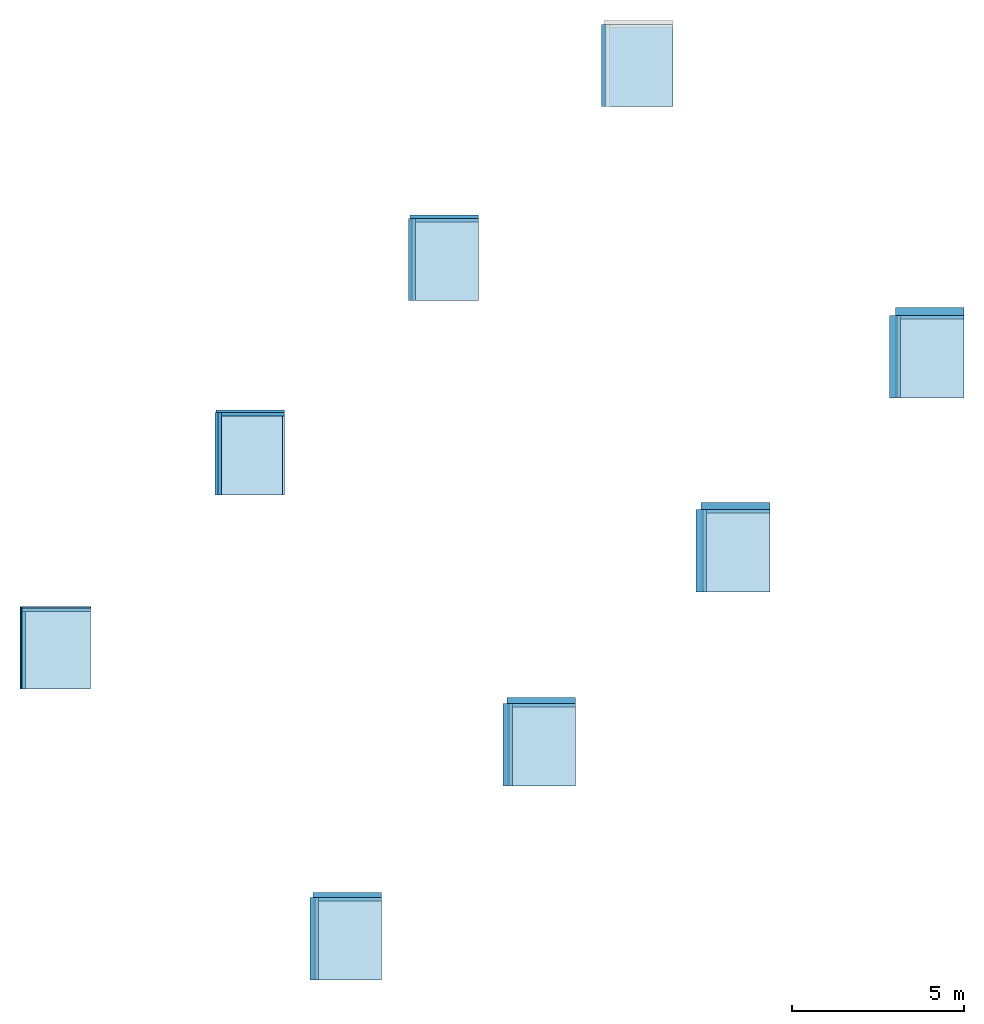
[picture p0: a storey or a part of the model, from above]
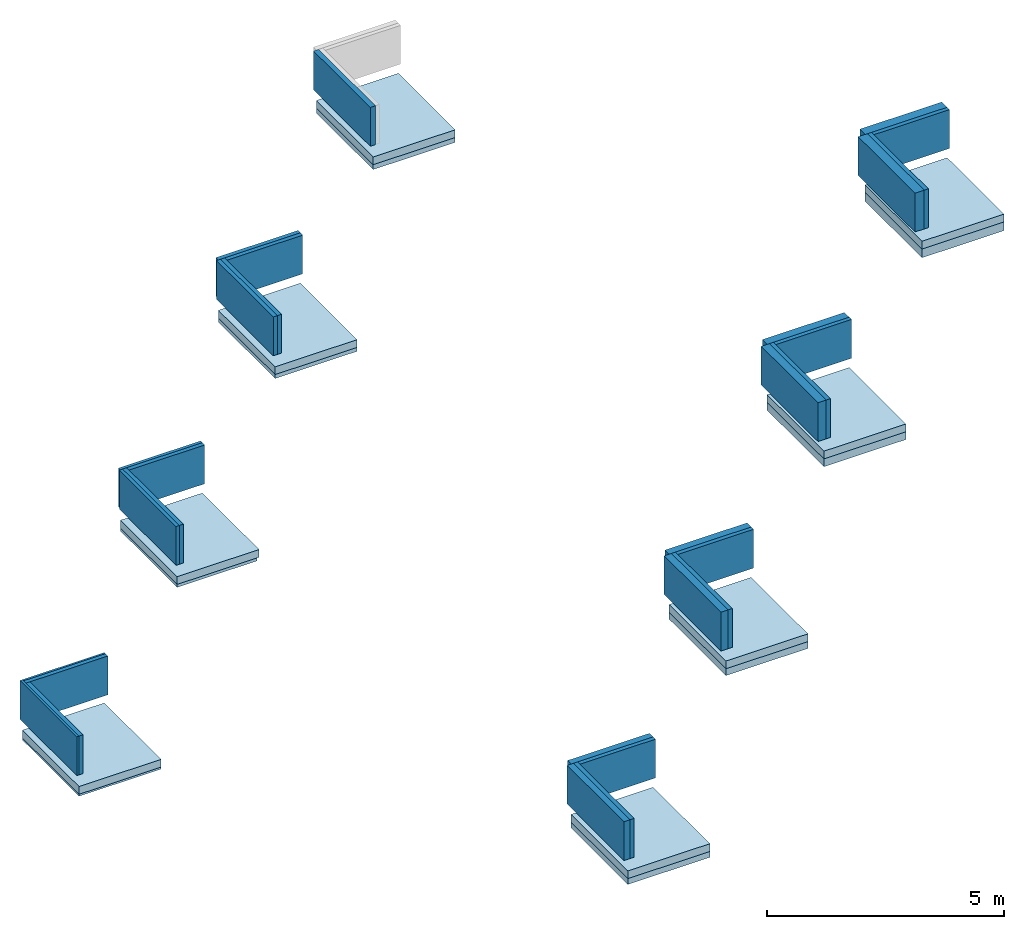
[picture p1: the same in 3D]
Properties of the parts of a building model (IFC2X3), part 2 of 2

# IfcWallStandardCase: Basic Wall:NLRS_41_WA_Heraklith Tektalan A2 SmartTec 125x1000x600mm, Basic Wall:NLRS_41_WA_Heraklith Tektalan A2 SmartTec 125x1000x600mm:929720
Type - Pset_Wall Schedule LOD400 - panelen per pallet: 8; Assembly Code: 41.10; Type Image: Raster image: Heraklith Tektalan A2.jpg; Model: Heraklith® | Tektalan A2 SmartTec is een A2 houtwolcementpaneel gecombineerd met een steenwol-plaat.; Manufacturer: Knauf Insulation B.V.; URL: www.heraklith.nl; Description: Tektalan A2 SmartTec - 125mm; phone: +31(0)162-421245; email: customerservice.nl@knaufinsulation.com; product URL: https://heraklith.nl/houtwol-producten/tektalan-a2-smarttec; warmteweerstand: 3,50 (m2.K/W); NLRS_C_Code_Brandklasse: A2-s1,d0; brandweerstand: REI 120/180 mits verwerkt tegen massief beton conform classificatierapport nr 18203 / 18204; geluidsabsorbtie: 1,00; DoP: W4302GPCPR; NLRS_C_content_creator: Knauf Insulation; NLRS_C_content_versie: V1.0; gewicht KG/M2: 19.5; pallet m2: 4.8 m2; vezelbreedte: standaard 2mm optie: 1mm; kleur: standaard natuurtint optie: Wit (RAL9003) / RAL; Druksterkte kPa: 30; Chloride gehalte: Cl3; Tolerantie: Dikte (T): (T1) +3/-2; Tolerantie: Lengte (L): (L2) +3/-5; Tolerantie: Breedte (W): (W1) +3/-3; Tolerantie: Haaksheid (S): (S2) ≤2; Tolerantie: Vlakheid (P): (P1) ≤6; Randafwerking: Isolatie: n.v.t.; Randafwerking: Houtwol: Facet: 5mm; CE-codering: WW-C2-EN 13168-L2-W1-T1-S2-P1-CS(10/Y)30-TR7,5-Cl3
Classification: 41.10 (Uniformat)
Pset_WallCommon - IsExternal: yes; ExtendToStructure: no; LoadBearing: no
Wall Schedule LOD200 - Type: Basic Wall: NLRS_41_WA_Heraklith Tektalan A2 SmartTec 125x1000x600mm
Pset_Wall Schedule LOD400 - Type: Basic Wall: NLRS_41_WA_Heraklith Tektalan A2 SmartTec 125x1000x600mm

# IfcWallStandardCase: Basic Wall:NLRS_41_WA_Heraklith Tektalan A2 SmartTec 150x1000x600mm, Basic Wall:NLRS_41_WA_Heraklith Tektalan A2 SmartTec 150x1000x600mm:929828
In: 00 begane grond
Type - PredefinedType: STANDARD; Material: Heraklith® I Tektalan A2 - Steenwol 140 mm, Heraklith® I Tektalan A2 - Houtwollaag - 1000x600mm 10 mm
Type - Pset_ElementShading - Roughness: 304.8 mm
Type - Pset_ManufacturerTypeInformation - Manufacturer: Knauf Insulation B.V.
Type - Pset_ProductRequirements - Category: Walls
Type - Pset_QuantityTakeOff - Reference: Basic Wall:NLRS_41_WA_Heraklith Tektalan A2 SmartTec 150x1000x600mm
Type - Pset_ReinforcementBarPitchOfWall - Description: Tektalan A2 SmartTec - 150mm; Reference: Basic Wall:NLRS_41_WA_Heraklith Tektalan A2 SmartTec 150x1000x600mm
Type - Pset_WallCommon - IsExternal: no; Reference: Basic Wall:NLRS_41_WA_Heraklith Tektalan A2 SmartTec 150x1000x600mm; ThermalTransmittance: 0.236111 kg/K/s3
Type - Wall Schedule LOD200 - Assembly Code: 41.10; Type Image: Raster image: Heraklith Tektalan A2.jpg; Model: Heraklith® | Tektalan A2 SmartTec is een A2 houtwolcementpaneel gecombineerd met een steenwol-plaat.; Manufacturer: Knauf Insulation B.V.; URL: www.heraklith.nl; Description: Tektalan A2 SmartTec - 150mm; phone: +31(0)162-421245; email: customerservice.nl@knaufinsulation.com; product URL: https://heraklith.nl/houtwol-producten/tektalan-a2-smarttec; warmteweerstand: 4,20 (m2.K/W); NLRS_C_Code_Brandklasse: A2-s1,d0; brandweerstand: REI 120/180 mits verwerkt tegen massief beton conform classificatierapport nr 18203 / 18204; geluidsabsorbtie: 1,00; DoP: W4302GPCPR; NLRS_C_content_creator: Knauf Insulation; NLRS_C_content_versie: V1.0
Type - Pset_Wall Schedule LOD400 - panelen per pallet: 7; Assembly Code: 41.10; Type Image: Raster image: Heraklith Tektalan A2.jpg; Model: Heraklith® | Tektalan A2 SmartTec is een A2 houtwolcementpaneel gecombineerd met een steenwol-plaat.; Manufacturer: Knauf Insulation B.V.; URL: www.heraklith.nl; Description: Tektalan A2 SmartTec - 150mm; phone: +31(0)162-421245; email: customerservice.nl@knaufinsulation.com; product URL: https://heraklith.nl/houtwol-producten/tektalan-a2-smarttec; warmteweerstand: 4,20 (m2.K/W); NLRS_C_Code_Brandklasse: A2-s1,d0; brandweerstand: REI 120/180 mits verwerkt tegen massief beton conform classificatierapport nr 18203 / 18204; geluidsabsorbtie: 1,00; DoP: W4302GPCPR; NLRS_C_content_creator: Knauf Insulation; NLRS_C_content_versie: V1.0; gewicht KG/M2: 22.5; pallet m2: 4.2 m2; vezelbreedte: standaard 2mm optie: 1mm; kleur: standaard natuurtint optie: Wit (RAL9003) / RAL; Druksterkte kPa: 30; Chloride gehalte: Cl3; Tolerantie: Dikte (T): (T1) +3/-2; Tolerantie: Lengte (L): (L2) +3/-5; Tolerantie: Breedte (W): (W1) +3/-3; Tolerantie: Haaksheid (S): (S2) ≤2; Tolerantie: Vlakheid (P): (P1) ≤6; Randafwerking: Isolatie: n.v.t.; Randafwerking: Houtwol: Facet: 5mm; CE-codering: WW-C2-EN 13168-L2-W1-T1-S2-P1-CS(10/Y)30-TR7,5-Cl3
Classification: 41.10 (Uniformat)
Pset_WallCommon - IsExternal: yes; ExtendToStructure: no; LoadBearing: no
Wall Schedule LOD200 - Type: Basic Wall: NLRS_41_WA_Heraklith Tektalan A2 SmartTec 150x1000x600mm
Pset_Wall Schedule LOD400 - Type: Basic Wall: NLRS_41_WA_Heraklith Tektalan A2 SmartTec 150x1000x600mm

# IfcWallStandardCase: Basic Wall:NLRS_41_WA_Heraklith Tektalan A2 SmartTec 175x1000x600mm, Basic Wall:NLRS_41_WA_Heraklith Tektalan A2 SmartTec 175x1000x600mm:929852
In: 00 begane grond
Type - PredefinedType: STANDARD; Material: Heraklith® I Tektalan A2 - Steenwol 165 mm, Heraklith® I Tektalan A2 - Houtwollaag - 1000x600mm 10 mm
Type - Pset_ElementShading - Roughness: 304.8 mm
Type - Pset_ManufacturerTypeInformation - Manufacturer: Knauf Insulation B.V.
Type - Pset_ProductRequirements - Category: Walls
Type - Pset_QuantityTakeOff - Reference: Basic Wall:NLRS_41_WA_Heraklith Tektalan A2 SmartTec 175x1000x600mm
Type - Pset_ReinforcementBarPitchOfWall - Description: Tektalan A2 SmartTec - 175mm; Reference: Basic Wall:NLRS_41_WA_Heraklith Tektalan A2 SmartTec 175x1000x600mm
Type - Pset_WallCommon - IsExternal: no; Reference: Basic Wall:NLRS_41_WA_Heraklith Tektalan A2 SmartTec 175x1000x600mm; ThermalTransmittance: 0.201183 kg/K/s3
Type - Wall Schedule LOD200 - Assembly Code: 41.10; Type Image: Raster image: Heraklith Tektalan A2.jpg; Model: Heraklith® | Tektalan A2 SmartTec is een A2 houtwolcementpaneel gecombineerd met een steenwol-plaat.; Manufacturer: Knauf Insulation B.V.; URL: www.heraklith.nl; Description: Tektalan A2 SmartTec - 175mm; phone: +31(0)162-421245; email: customerservice.nl@knaufinsulation.com; product URL: https://heraklith.nl/houtwol-producten/tektalan-a2-smarttec; warmteweerstand: 4,95 (m2.K/W); NLRS_C_Code_Brandklasse: A2-s1,d0; brandweerstand: REI 120/180 mits verwerkt tegen massief beton conform classificatierapport nr 18203 / 18204; geluidsabsorbtie: 1,00; DoP: W4302GPCPR; NLRS_C_content_creator: Knauf Insulation; NLRS_C_content_versie: V1.0
Type - Pset_Wall Schedule LOD400 - panelen per pallet: 6; Assembly Code: 41.10; Type Image: Raster image: Heraklith Tektalan A2.jpg; Model: Heraklith® | Tektalan A2 SmartTec is een A2 houtwolcementpaneel gecombineerd met een steenwol-plaat.; Manufacturer: Knauf Insulation B.V.; URL: www.heraklith.nl; Description: Tektalan A2 SmartTec - 175mm; phone: +31(0)162-421245; email: customerservice.nl@knaufinsulation.com; product URL: https://heraklith.nl/houtwol-producten/tektalan-a2-smarttec; warmteweerstand: 4,95 (m2.K/W); NLRS_C_Code_Brandklasse: A2-s1,d0; brandweerstand: REI 120/180 mits verwerkt tegen massief beton conform classificatierapport nr 18203 / 18204; geluidsabsorbtie: 1,00; DoP: W4302GPCPR; NLRS_C_content_creator: Knauf Insulation; NLRS_C_content_versie: V1.0; gewicht KG/M2: 25; pallet m2: 3.6 m2; vezelbreedte: standaard 2mm optie: 1mm; kleur: standaard natuurtint optie: Wit (RAL9003) / RAL; Druksterkte kPa: 30; Chloride gehalte: Cl3; Tolerantie: Dikte (T): (T1) +3/-2; Tolerantie: Lengte (L): (L2) +3/-5; Tolerantie: Breedte (W): (W1) +3/-3; Tolerantie: Haaksheid (S): (S2) ≤2; Tolerantie: Vlakheid (P): (P1) ≤6; Randafwerking: Isolatie: n.v.t.; Randafwerking: Houtwol: Facet: 5mm; CE-codering: WW-C2-EN 13168-L2-W1-T1-S2-P1-CS(10/Y)30-TR7,5-Cl3
Classification: 41.10 (Uniformat)
Pset_WallCommon - IsExternal: yes; ExtendToStructure: no; LoadBearing: no
Wall Schedule LOD200 - Type: Basic Wall: NLRS_41_WA_Heraklith Tektalan A2 SmartTec 175x1000x600mm
Pset_Wall Schedule LOD400 - Type: Basic Wall: NLRS_41_WA_Heraklith Tektalan A2 SmartTec 175x1000x600mm

# IfcWallStandardCase: Basic Wall:NLRS_41_WA_Heraklith Tektalan A2 SmartTec 200x1000x600mm, Basic Wall:NLRS_41_WA_Heraklith Tektalan A2 SmartTec 200x1000x600mm:929877
In: 00 begane grond
Type - PredefinedType: STANDARD; Material: Heraklith® I Tektalan A2 - Steenwol 190 mm, Heraklith® I Tektalan A2 - Houtwollaag - 1000x600mm 10 mm
Type - Pset_ElementShading - Roughness: 304.8 mm
Type - Pset_ManufacturerTypeInformation - Manufacturer: Knauf Insulation B.V.
Type - Pset_ProductRequirements - Category: Walls
Type - Pset_QuantityTakeOff - Reference: Basic Wall:NLRS_41_WA_Heraklith Tektalan A2 SmartTec 200x1000x600mm
Type - Pset_ReinforcementBarPitchOfWall - Description: Tektalan A2 SmartTec - 200mm; Reference: Basic Wall:NLRS_41_WA_Heraklith Tektalan A2 SmartTec 200x1000x600mm
Type - Pset_WallCommon - IsExternal: no; Reference: Basic Wall:NLRS_41_WA_Heraklith Tektalan A2 SmartTec 200x1000x600mm; ThermalTransmittance: 0.175258 kg/K/s3
Type - Wall Schedule LOD200 - Assembly Code: 41.10; Type Image: Raster image: Heraklith Tektalan A2.jpg; Model: Heraklith® | Tektalan A2 SmartTec is een A2 houtwolcementpaneel gecombineerd met een steenwol-plaat.; Manufacturer: Knauf Insulation B.V.; URL: www.heraklith.nl; Description: Tektalan A2 SmartTec - 200mm; phone: +31(0)162-421245; email: customerservice.nl@knaufinsulation.com; product URL: https://heraklith.nl/houtwol-producten/tektalan-a2-smarttec; warmteweerstand: 5,70 (m2.K/W); NLRS_C_Code_Brandklasse: A2-s1,d0; brandweerstand: REI 120/180 mits verwerkt tegen massief beton conform classificatierapport nr 18203 / 18204; geluidsabsorbtie: 0,95; DoP: W4302GPCPR; NLRS_C_content_creator: Knauf Insulation; NLRS_C_content_versie: V1.0
Type - Pset_Wall Schedule LOD400 - panelen per pallet: 5; Assembly Code: 41.10; Type Image: Raster image: Heraklith Tektalan A2.jpg; Model: Heraklith® | Tektalan A2 SmartTec is een A2 houtwolcementpaneel gecombineerd met een steenwol-plaat.; Manufacturer: Knauf Insulation B.V.; URL: www.heraklith.nl; Description: Tektalan A2 SmartTec - 200mm; phone: +31(0)162-421245; email: customerservice.nl@knaufinsulation.com; product URL: https://heraklith.nl/houtwol-producten/tektalan-a2-smarttec; warmteweerstand: 5,70 (m2.K/W); NLRS_C_Code_Brandklasse: A2-s1,d0; brandweerstand: REI 120/180 mits verwerkt tegen massief beton conform classificatierapport nr 18203 / 18204; geluidsabsorbtie: 0,95; DoP: W4302GPCPR; NLRS_C_content_creator: Knauf Insulation; NLRS_C_content_versie: V1.0; gewicht KG/M2: 25.5; pallet m2: 3 m2; vezelbreedte: standaard 2mm optie: 1mm; kleur: standaard natuurtint optie: Wit (RAL9003) / RAL; Druksterkte kPa: 30; Chloride gehalte: Cl3; Tolerantie: Dikte (T): (T1) +3/-2; Tolerantie: Lengte (L): (L2) +3/-5; Tolerantie: Breedte (W): (W1) +3/-3; Tolerantie: Haaksheid (S): (S2) ≤2; Tolerantie: Vlakheid (P): (P1) ≤6; Randafwerking: Isolatie: n.v.t.; Randafwerking: Houtwol: Facet: 5mm; CE-codering: WW-C2-EN 13168-L2-W1-T1-S2-P1-CS(10/Y)30-TR7,5-Cl3
Classification: 41.10 (Uniformat)
Pset_WallCommon - IsExternal: yes; ExtendToStructure: no; LoadBearing: no
Wall Schedule LOD200 - Type: Basic Wall: NLRS_41_WA_Heraklith Tektalan A2 SmartTec 200x1000x600mm
Pset_Wall Schedule LOD400 - Type: Basic Wall: NLRS_41_WA_Heraklith Tektalan A2 SmartTec 200x1000x600mm

# IfcWallStandardCase: Basic Wall:NLRS_41_WA_Heraklith Tektalan A2 SmartTec 225x1000x600mm, Basic Wall:NLRS_41_WA_Heraklith Tektalan A2 SmartTec 225x1000x600mm:929902
In: 00 begane grond
Type - PredefinedType: STANDARD; Material: Heraklith® I Tektalan A2 - Steenwol 215 mm, Heraklith® I Tektalan A2 - Houtwollaag - 1000x600mm 10 mm
Type - Pset_ElementShading - Roughness: 304.8 mm
Type - Pset_ManufacturerTypeInformation - Manufacturer: Knauf Insulation B.V.
Type - Pset_ProductRequirements - Category: Walls
Type - Pset_QuantityTakeOff - Reference: Basic Wall:NLRS_41_WA_Heraklith Tektalan A2 SmartTec 225x1000x600mm
Type - Pset_ReinforcementBarPitchOfWall - Description: Tektalan A2 SmartTec - 225mm; Reference: Basic Wall:NLRS_41_WA_Heraklith Tektalan A2 SmartTec 225x1000x600mm
Type - Pset_WallCommon - IsExternal: no; Reference: Basic Wall:NLRS_41_WA_Heraklith Tektalan A2 SmartTec 225x1000x600mm; ThermalTransmittance: 0.155251 kg/K/s3
Type - Wall Schedule LOD200 - Assembly Code: 41.10; Type Image: Raster image: Heraklith Tektalan A2.jpg; Model: Heraklith® | Tektalan A2 SmartTec is een A2 houtwolcementpaneel gecombineerd met een steenwol-plaat.; Manufacturer: Knauf Insulation B.V.; URL: www.heraklith.nl; Description: Tektalan A2 SmartTec - 225mm; phone: +31(0)162-421245; email: customerservice.nl@knaufinsulation.com; product URL: https://heraklith.nl/houtwol-producten/tektalan-a2-smarttec; warmteweerstand: 6,40 (m2.K/W); NLRS_C_Code_Brandklasse: A2-s1,d0; brandweerstand: REI 120/180 mits verwerkt tegen massief beton conform classificatierapport nr 18203 / 18204; geluidsabsorbtie: 0,95; DoP: W4302GPCPR; NLRS_C_content_creator: Knauf Insulation; NLRS_C_content_versie: V1.0
Type - Pset_Wall Schedule LOD400 - panelen per pallet: 5; Assembly Code: 41.10; Type Image: Raster image: Heraklith Tektalan A2.jpg; Model: Heraklith® | Tektalan A2 SmartTec is een A2 houtwolcementpaneel gecombineerd met een steenwol-plaat.; Manufacturer: Knauf Insulation B.V.; URL: www.heraklith.nl; Description: Tektalan A2 SmartTec - 225mm; phone: +31(0)162-421245; email: customerservice.nl@knaufinsulation.com; product URL: https://heraklith.nl/houtwol-producten/tektalan-a2-smarttec; warmteweerstand: 6,40 (m2.K/W); NLRS_C_Code_Brandklasse: A2-s1,d0; brandweerstand: REI 120/180 mits verwerkt tegen massief beton conform classificatierapport nr 18203 / 18204; geluidsabsorbtie: 0,95; DoP: W4302GPCPR; NLRS_C_content_creator: Knauf Insulation; NLRS_C_content_versie: V1.0; gewicht KG/M2: 31; pallet m2: 3 m2; vezelbreedte: standaard 2mm optie: 1mm; kleur: standaard natuurtint optie: Wit (RAL9003) / RAL; Druksterkte kPa: 30; Chloride gehalte: Cl3; Tolerantie: Dikte (T): (T1) +3/-2; Tolerantie: Lengte (L): (L2) +3/-5; Tolerantie: Breedte (W): (W1) +3/-3; Tolerantie: Haaksheid (S): (S2) ≤2; Tolerantie: Vlakheid (P): (P1) ≤6; Randafwerking: Isolatie: n.v.t.; Randafwerking: Houtwol: Facet: 5mm; CE-codering: WW-C2-EN 13168-L2-W1-T1-S2-P1-CS(10/Y)30-TR7,5-Cl3
Classification: 41.10 (Uniformat)
Pset_WallCommon - IsExternal: yes; ExtendToStructure: no; LoadBearing: no
Wall Schedule LOD200 - Type: Basic Wall: NLRS_41_WA_Heraklith Tektalan A2 SmartTec 225x1000x600mm
Pset_Wall Schedule LOD400 - Type: Basic Wall: NLRS_41_WA_Heraklith Tektalan A2 SmartTec 225x1000x600mm

# IfcWallStandardCase: Basic Wall:NLRS_41_WA_Heraklith Tektalan A2 SmartTec 50x1000x600mm, Basic Wall:NLRS_41_WA_Heraklith Tektalan A2 SmartTec 50x1000x600mm:905813
In: 00 begane grond
Type - PredefinedType: STANDARD; Material: Heraklith® I Tektalan A2 - Steenwol 40 mm, Heraklith® I Tektalan A2 - Houtwollaag - 1000x600mm 10 mm
Type - Pset_ElementShading - Roughness: 304.8 mm
Type - Pset_ManufacturerTypeInformation - Manufacturer: Knauf Insulation B.V.
Type - Pset_ProductRequirements - Category: Walls
Type - Pset_QuantityTakeOff - Reference: Basic Wall:NLRS_41_WA_Heraklith Tektalan A2 SmartTec 50x1000x600mm
Type - Pset_ReinforcementBarPitchOfWall - Description: Tektalan A2 SmartTec - 50mm; Reference: Basic Wall:NLRS_41_WA_Heraklith Tektalan A2 SmartTec 50x1000x600mm
Type - Pset_WallCommon - Reference: Basic Wall:NLRS_41_WA_Heraklith Tektalan A2 SmartTec 50x1000x600mm; ThermalTransmittance: 0.772727 kg/K/s3; IsExternal: no
Type - Wall Schedule LOD200 - Assembly Code: 41.10; Type Image: Raster image: Heraklith Tektalan A2.jpg; Model: Heraklith® | Tektalan A2 SmartTec is een A2 houtwolcementpaneel gecombineerd met een steenwol-plaat.; Manufacturer: Knauf Insulation B.V.; URL: www.heraklith.nl; Description: Tektalan A2 SmartTec - 50mm; phone: +31(0)162-421245; email: customerservice.nl@knaufinsulation.com; product URL: https://heraklith.nl/houtwol-producten/tektalan-a2-smarttec; warmteweerstand: 1,25 (m2.K/W); NLRS_C_Code_Brandklasse: A2-s1,d0; brandweerstand: REI 120/180 mits verwerkt tegen massief beton conform classificatierapport nr 18203 / 18204; geluidsabsorbtie: 0,95; DoP: W4302GPCPR; NLRS_C_content_creator: Knauf Insulation; NLRS_C_content_versie: V1.0
Type - Pset_Wall Schedule LOD400 - Assembly Code: 41.10; Type Image: Raster image: Heraklith Tektalan A2.jpg; Model: Heraklith® | Tektalan A2 SmartTec is een A2 houtwolcementpaneel gecombineerd met een steenwol-plaat.; Manufacturer: Knauf Insulation B.V.; URL: www.heraklith.nl; Description: Tektalan A2 SmartTec - 50mm; phone: +31(0)162-421245; email: customerservice.nl@knaufinsulation.com; product URL: https://heraklith.nl/houtwol-producten/tektalan-a2-smarttec; warmteweerstand: 1,25 (m2.K/W); NLRS_C_Code_Brandklasse: A2-s1,d0; brandweerstand: REI 120/180 mits verwerkt tegen massief beton conform classificatierapport nr 18203 / 18204; geluidsabsorbtie: 0,95; DoP: W4302GPCPR; NLRS_C_content_creator: Knauf Insulation; NLRS_C_content_versie: V1.0; gewicht KG/M2: 11; panelen per pallet: 22; pallet m2: 13.2 m2; vezelbreedte: standaard 2mm optie: 1mm; kleur: standaard natuurtint optie: Wit (RAL9003) / RAL; Druksterkte kPa: 30; Chloride gehalte: Cl3; Tolerantie: Dikte (T): (T1) +3/-2; Tolerantie: Lengte (L): (L2) +3/-5; Tolerantie: Breedte (W): (W1) +3/-3; Tolerantie: Haaksheid (S): (S2) ≤2; Tolerantie: Vlakheid (P): (P1) ≤6; Randafwerking: Isolatie: n.v.t.; Randafwerking: Houtwol: Facet: 5mm; CE-codering: WW-C2-EN 13168-L2-W1-T1-S2-P1-CS(10/Y)30-TR7,5-Cl3
Classification: 41.10 (Uniformat)
Pset_WallCommon - IsExternal: yes; ExtendToStructure: no; LoadBearing: no
Wall Schedule LOD200 - Type: Basic Wall: NLRS_41_WA_Heraklith Tektalan A2 SmartTec 50x1000x600mm
Pset_Wall Schedule LOD400 - Type: Basic Wall: NLRS_41_WA_Heraklith Tektalan A2 SmartTec 50x1000x600mm

# IfcWallStandardCase: Basic Wall:NLRS_41_WA_Heraklith Tektalan A2 SmartTec 75x1000x600mm, Basic Wall:NLRS_41_WA_Heraklith Tektalan A2 SmartTec 75x1000x600mm:929507
In: 00 begane grond
Type - PredefinedType: STANDARD; Material: Heraklith® I Tektalan A2 - Steenwol 65 mm, Heraklith® I Tektalan A2 - Houtwollaag - 1000x600mm 10 mm
Type - Pset_ElementShading - Roughness: 304.8 mm
Type - Pset_ManufacturerTypeInformation - Manufacturer: Knauf Insulation B.V.
Type - Pset_ProductRequirements - Category: Walls
Type - Pset_QuantityTakeOff - Reference: Basic Wall:NLRS_41_WA_Heraklith Tektalan A2 SmartTec 75x1000x600mm
Type - Pset_ReinforcementBarPitchOfWall - Description: Tektalan A2 SmartTec - 75mm; Reference: Basic Wall:NLRS_41_WA_Heraklith Tektalan A2 SmartTec 75x1000x600mm
Type - Pset_WallCommon - IsExternal: no; Reference: Basic Wall:NLRS_41_WA_Heraklith Tektalan A2 SmartTec 75x1000x600mm; ThermalTransmittance: 0.492754 kg/K/s3
Type - Wall Schedule LOD200 - Assembly Code: 41.10; Type Image: Raster image: Heraklith Tektalan A2.jpg; Model: Heraklith® | Tektalan A2 SmartTec is een A2 houtwolcementpaneel gecombineerd met een steenwol-plaat.; Manufacturer: Knauf Insulation B.V.; URL: www.heraklith.nl; Description: Tektalan A2 SmartTec - 75mm; phone: +31(0)162-421245; email: customerservice.nl@knaufinsulation.com; product URL: https://heraklith.nl/houtwol-producten/tektalan-a2-smarttec; warmteweerstand: 2,00 (m2.K/W); NLRS_C_Code_Brandklasse: A2-s1,d0; brandweerstand: REI 120/180 mits verwerkt tegen massief beton conform classificatierapport nr 18203 / 18204; geluidsabsorbtie: 0,95; DoP: W4302GPCPR; NLRS_C_content_creator: Knauf Insulation; NLRS_C_content_versie: V1.0
Type - Pset_Wall Schedule LOD400 - Assembly Code: 41.10; Type Image: Raster image: Heraklith Tektalan A2.jpg; Model: Heraklith® | Tektalan A2 SmartTec is een A2 houtwolcementpaneel gecombineerd met een steenwol-plaat.; Manufacturer: Knauf Insulation B.V.; URL: www.heraklith.nl; Description: Tektalan A2 SmartTec - 75mm; phone: +31(0)162-421245; email: customerservice.nl@knaufinsulation.com; product URL: https://heraklith.nl/houtwol-producten/tektalan-a2-smarttec; warmteweerstand: 2,00 (m2.K/W); NLRS_C_Code_Brandklasse: A2-s1,d0; brandweerstand: REI 120/180 mits verwerkt tegen massief beton conform classificatierapport nr 18203 / 18204; geluidsabsorbtie: 0,95; DoP: W4302GPCPR; NLRS_C_content_creator: Knauf Insulation; NLRS_C_content_versie: V1.0; gewicht KG/M2: 14; panelen per pallet: 14; pallet m2: 8.4 m2; vezelbreedte: standaard 2mm optie: 1mm; kleur: standaard natuurtint optie: Wit (RAL9003) / RAL; Druksterkte kPa: 30; Chloride gehalte: Cl3; Tolerantie: Dikte (T): (T1) +3/-2; Tolerantie: Lengte (L): (L2) +3/-5; Tolerantie: Breedte (W): (W1) +3/-3; Tolerantie: Haaksheid (S): (S2) ≤2; Tolerantie: Vlakheid (P): (P1) ≤6; Randafwerking: Isolatie: n.v.t.; Randafwerking: Houtwol: Facet: 5mm; CE-codering: WW-C2-EN 13168-L2-W1-T1-S2-P1-CS(10/Y)30-TR7,5-Cl3
Classification: 41.10 (Uniformat)
Pset_WallCommon - IsExternal: yes; ExtendToStructure: no; LoadBearing: no
Wall Schedule LOD200 - Type: Basic Wall: NLRS_41_WA_Heraklith Tektalan A2 SmartTec 75x1000x600mm
Pset_Wall Schedule LOD400 - Type: Basic Wall: NLRS_41_WA_Heraklith Tektalan A2 SmartTec 75x1000x600mm

# IfcWallStandardCase: Basic Wall:NLRS_42_WA_Heraklith Tektalan A2 SmartTec 100x1000x600mm, Basic Wall:NLRS_42_WA_Heraklith Tektalan A2 SmartTec 100x1000x600mm:929629
In: 00 begane grond
Type - PredefinedType: STANDARD; Material: Heraklith® I Tektalan A2 - Steenwol 90 mm, Heraklith® I Tektalan A2 - Houtwollaag - 1000x600mm 10 mm
Type - Pset_ElementShading - Roughness: 304.8 mm
Type - Pset_ManufacturerTypeInformation - Manufacturer: Knauf Insulation B.V.
Type - Pset_ProductRequirements - Category: Walls
Type - Pset_QuantityTakeOff - Reference: Basic Wall:NLRS_42_WA_Heraklith Tektalan A2 SmartTec 100x1000x600mm
Type - Pset_ReinforcementBarPitchOfWall - Description: Tektalan A2 SmartTec - 100mm; Reference: Basic Wall:NLRS_42_WA_Heraklith Tektalan A2 SmartTec 100x1000x600mm
Type - Pset_WallCommon - IsExternal: no; Reference: Basic Wall:NLRS_42_WA_Heraklith Tektalan A2 SmartTec 100x1000x600mm; ThermalTransmittance: 0.361702 kg/K/s3
Type - Wall Schedule LOD200 - Assembly Code: 42.10; Type Image: Raster image: Heraklith Tektalan A2.jpg; Model: Heraklith® | Tektalan A2 SmartTec is een A2 houtwolcementpaneel gecombineerd met een steenwol-plaat.; Manufacturer: Knauf Insulation B.V.; URL: www.heraklith.nl; Description: Tektalan A2 SmartTec - 100mm; phone: +31(0)162-421245; email: customerservice.nl@knaufinsulation.com; product URL: https://heraklith.nl/houtwol-producten/tektalan-a2-smarttec; warmteweerstand: 2,75 (m2.K/W); NLRS_C_Code_Brandklasse: A2-s1,d0; brandweerstand: REI 120/180 mits verwerkt tegen massief beton conform classificatierapport nr 18203 / 18204; geluidsabsorbtie: 1,00; DoP: W4302GPCPR; NLRS_C_content_creator: Knauf Insulation; NLRS_C_content_versie: V1.0
Type - Pset_Wall Schedule LOD400 - Assembly Code: 42.10; Type Image: Raster image: Heraklith Tektalan A2.jpg; Model: Heraklith® | Tektalan A2 SmartTec is een A2 houtwolcementpaneel gecombineerd met een steenwol-plaat.; Manufacturer: Knauf Insulation B.V.; URL: www.heraklith.nl; Description: Tektalan A2 SmartTec - 100mm; phone: +31(0)162-421245; email: customerservice.nl@knaufinsulation.com; product URL: https://heraklith.nl/houtwol-producten/tektalan-a2-smarttec; warmteweerstand: 2,75 (m2.K/W); NLRS_C_Code_Brandklasse: A2-s1,d0; brandweerstand: REI 120/180 mits verwerkt tegen massief beton conform classificatierapport nr 18203 / 18204; geluidsabsorbtie: 1,00; DoP: W4302GPCPR; NLRS_C_content_creator: Knauf Insulation; NLRS_C_content_versie: V1.0; gewicht KG/M2: 17; panelen per pallet: 11; pallet m2: 6.6 m2; vezelbreedte: standaard 2mm optie: 1mm; kleur: standaard natuurtint optie: Wit (RAL9003) / RAL; Druksterkte kPa: 30; Chloride gehalte: Cl3; Tolerantie: Dikte (T): (T1) +3/-2; Tolerantie: Lengte (L): (L2) +3/-5; Tolerantie: Breedte (W): (W1) +3/-3; Tolerantie: Haaksheid (S): (S2) ≤2; Tolerantie: Vlakheid (P): (P1) ≤6; Randafwerking: Isolatie: n.v.t.; Randafwerking: Houtwol: Facet: 5mm; CE-codering: WW-C2-EN 13168-L2-W1-T1-S2-P1-CS(10/Y)30-TR7,5-Cl3
Classification: 42.10 (Uniformat)
Pset_WallCommon - ExtendToStructure: no; LoadBearing: no
Wall Schedule LOD200 - Type: Basic Wall: NLRS_42_WA_Heraklith Tektalan A2 SmartTec 100x1000x600mm
Pset_Wall Schedule LOD400 - Type: Basic Wall: NLRS_42_WA_Heraklith Tektalan A2 SmartTec 100x1000x600mm

# IfcWallStandardCase: Basic Wall:NLRS_42_WA_Heraklith Tektalan A2 SmartTec 125x1000x600mm, Basic Wall:NLRS_42_WA_Heraklith Tektalan A2 SmartTec 125x1000x600mm:929729
In: 00 begane grond
Type - PredefinedType: STANDARD; Material: Heraklith® I Tektalan A2 - Steenwol 115 mm, Heraklith® I Tektalan A2 - Houtwollaag - 1000x600mm 10 mm
Type - Pset_ElementShading - Roughness: 304.8 mm
Type - Pset_ManufacturerTypeInformation - Manufacturer: Knauf Insulation B.V.
Type - Pset_ProductRequirements - Category: Walls
Type - Pset_QuantityTakeOff - Reference: Basic Wall:NLRS_42_WA_Heraklith Tektalan A2 SmartTec 125x1000x600mm
Type - Pset_ReinforcementBarPitchOfWall - Description: Tektalan A2 SmartTec - 125mm; Reference: Basic Wall:NLRS_42_WA_Heraklith Tektalan A2 SmartTec 125x1000x600mm
Type - Pset_WallCommon - IsExternal: no; Reference: Basic Wall:NLRS_42_WA_Heraklith Tektalan A2 SmartTec 125x1000x600mm; ThermalTransmittance: 0.285714 kg/K/s3
Type - Wall Schedule LOD200 - Assembly Code: 42.10; Type Image: Raster image: Heraklith Tektalan A2.jpg; Model: Heraklith® | Tektalan A2 SmartTec is een A2 houtwolcementpaneel gecombineerd met een steenwol-plaat.; Manufacturer: Knauf Insulation B.V.; URL: www.heraklith.nl; Description: Tektalan A2 SmartTec - 125mm; phone: +31(0)162-421245; email: customerservice.nl@knaufinsulation.com; product URL: https://heraklith.nl/houtwol-producten/tektalan-a2-smarttec; warmteweerstand: 3,50 (m2.K/W); NLRS_C_Code_Brandklasse: A2-s1,d0; brandweerstand: REI 120/180 mits verwerkt tegen massief beton conform classificatierapport nr 18203 / 18204; geluidsabsorbtie: 1,00; DoP: W4302GPCPR; NLRS_C_content_creator: Knauf Insulation; NLRS_C_content_versie: V1.0
Type - Pset_Wall Schedule LOD400 - panelen per pallet: 8; Assembly Code: 42.10; Type Image: Raster image: Heraklith Tektalan A2.jpg; Model: Heraklith® | Tektalan A2 SmartTec is een A2 houtwolcementpaneel gecombineerd met een steenwol-plaat.; Manufacturer: Knauf Insulation B.V.; URL: www.heraklith.nl; Description: Tektalan A2 SmartTec - 125mm; phone: +31(0)162-421245; email: customerservice.nl@knaufinsulation.com; product URL: https://heraklith.nl/houtwol-producten/tektalan-a2-smarttec; warmteweerstand: 3,50 (m2.K/W); NLRS_C_Code_Brandklasse: A2-s1,d0; brandweerstand: REI 120/180 mits verwerkt tegen massief beton conform classificatierapport nr 18203 / 18204; geluidsabsorbtie: 1,00; DoP: W4302GPCPR; NLRS_C_content_creator: Knauf Insulation; NLRS_C_content_versie: V1.0; gewicht KG/M2: 19.5; pallet m2: 4.8 m2; vezelbreedte: standaard 2mm optie: 1mm; kleur: standaard natuurtint optie: Wit (RAL9003) / RAL; Druksterkte kPa: 30; Chloride gehalte: Cl3; Tolerantie: Dikte (T): (T1) +3/-2; Tolerantie: Lengte (L): (L2) +3/-5; Tolerantie: Breedte (W): (W1) +3/-3; Tolerantie: Haaksheid (S): (S2) ≤2; Tolerantie: Vlakheid (P): (P1) ≤6; Randafwerking: Isolatie: n.v.t.; Randafwerking: Houtwol: Facet: 5mm; CE-codering: WW-C2-EN 13168-L2-W1-T1-S2-P1-CS(10/Y)30-TR7,5-Cl3
Classification: 42.10 (Uniformat)
Pset_WallCommon - ExtendToStructure: no; LoadBearing: no
Wall Schedule LOD200 - Type: Basic Wall: NLRS_42_WA_Heraklith Tektalan A2 SmartTec 125x1000x600mm
Pset_Wall Schedule LOD400 - Type: Basic Wall: NLRS_42_WA_Heraklith Tektalan A2 SmartTec 125x1000x600mm

# IfcWallStandardCase: Basic Wall:NLRS_42_WA_Heraklith Tektalan A2 SmartTec 150x1000x600mm, Basic Wall:NLRS_42_WA_Heraklith Tektalan A2 SmartTec 150x1000x600mm:929837
In: 00 begane grond
Type - PredefinedType: STANDARD; Material: Heraklith® I Tektalan A2 - Steenwol 140 mm, Heraklith® I Tektalan A2 - Houtwollaag - 1000x600mm 10 mm
Type - Pset_ElementShading - Roughness: 304.8 mm
Type - Pset_ManufacturerTypeInformation - Manufacturer: Knauf Insulation B.V.
Type - Pset_ProductRequirements - Category: Walls
Type - Pset_QuantityTakeOff - Reference: Basic Wall:NLRS_42_WA_Heraklith Tektalan A2 SmartTec 150x1000x600mm
Type - Pset_ReinforcementBarPitchOfWall - Description: Tektalan A2 SmartTec - 150mm; Reference: Basic Wall:NLRS_42_WA_Heraklith Tektalan A2 SmartTec 150x1000x600mm
Type - Pset_WallCommon - IsExternal: no; Reference: Basic Wall:NLRS_42_WA_Heraklith Tektalan A2 SmartTec 150x1000x600mm; ThermalTransmittance: 0.236111 kg/K/s3
Type - Wall Schedule LOD200 - Assembly Code: 42.10; Type Image: Raster image: Heraklith Tektalan A2.jpg; Model: Heraklith® | Tektalan A2 SmartTec is een A2 houtwolcementpaneel gecombineerd met een steenwol-plaat.; Manufacturer: Knauf Insulation B.V.; URL: www.heraklith.nl; Description: Tektalan A2 SmartTec - 150mm; phone: +31(0)162-421245; email: customerservice.nl@knaufinsulation.com; product URL: https://heraklith.nl/houtwol-producten/tektalan-a2-smarttec; warmteweerstand: 4,20 (m2.K/W); NLRS_C_Code_Brandklasse: A2-s1,d0; brandweerstand: REI 120/180 mits verwerkt tegen massief beton conform classificatierapport nr 18203 / 18204; geluidsabsorbtie: 1,00; DoP: W4302GPCPR; NLRS_C_content_creator: Knauf Insulation; NLRS_C_content_versie: V1.0
Type - Pset_Wall Schedule LOD400 - panelen per pallet: 7; Assembly Code: 42.10; Type Image: Raster image: Heraklith Tektalan A2.jpg; Model: Heraklith® | Tektalan A2 SmartTec is een A2 houtwolcementpaneel gecombineerd met een steenwol-plaat.; Manufacturer: Knauf Insulation B.V.; URL: www.heraklith.nl; Description: Tektalan A2 SmartTec - 150mm; phone: +31(0)162-421245; email: customerservice.nl@knaufinsulation.com; product URL: https://heraklith.nl/houtwol-producten/tektalan-a2-smarttec; warmteweerstand: 4,20 (m2.K/W); NLRS_C_Code_Brandklasse: A2-s1,d0; brandweerstand: REI 120/180 mits verwerkt tegen massief beton conform classificatierapport nr 18203 / 18204; geluidsabsorbtie: 1,00; DoP: W4302GPCPR; NLRS_C_content_creator: Knauf Insulation; NLRS_C_content_versie: V1.0; gewicht KG/M2: 22.5; pallet m2: 4.2 m2; vezelbreedte: standaard 2mm optie: 1mm; kleur: standaard natuurtint optie: Wit (RAL9003) / RAL; Druksterkte kPa: 30; Chloride gehalte: Cl3; Tolerantie: Dikte (T): (T1) +3/-2; Tolerantie: Lengte (L): (L2) +3/-5; Tolerantie: Breedte (W): (W1) +3/-3; Tolerantie: Haaksheid (S): (S2) ≤2; Tolerantie: Vlakheid (P): (P1) ≤6; Randafwerking: Isolatie: n.v.t.; Randafwerking: Houtwol: Facet: 5mm; CE-codering: WW-C2-EN 13168-L2-W1-T1-S2-P1-CS(10/Y)30-TR7,5-Cl3
Classification: 42.10 (Uniformat)
Pset_WallCommon - ExtendToStructure: no; LoadBearing: no
Wall Schedule LOD200 - Type: Basic Wall: NLRS_42_WA_Heraklith Tektalan A2 SmartTec 150x1000x600mm
Pset_Wall Schedule LOD400 - Type: Basic Wall: NLRS_42_WA_Heraklith Tektalan A2 SmartTec 150x1000x600mm

# IfcWallStandardCase: Basic Wall:NLRS_42_WA_Heraklith Tektalan A2 SmartTec 175x1000x600mm, Basic Wall:NLRS_42_WA_Heraklith Tektalan A2 SmartTec 175x1000x600mm:929861
In: 00 begane grond
Type - PredefinedType: STANDARD; Material: Heraklith® I Tektalan A2 - Steenwol 165 mm, Heraklith® I Tektalan A2 - Houtwollaag - 1000x600mm 10 mm
Type - Pset_ElementShading - Roughness: 304.8 mm
Type - Pset_ManufacturerTypeInformation - Manufacturer: Knauf Insulation B.V.
Type - Pset_ProductRequirements - Category: Walls
Type - Pset_QuantityTakeOff - Reference: Basic Wall:NLRS_42_WA_Heraklith Tektalan A2 SmartTec 175x1000x600mm
Type - Pset_ReinforcementBarPitchOfWall - Description: Tektalan A2 SmartTec - 175mm; Reference: Basic Wall:NLRS_42_WA_Heraklith Tektalan A2 SmartTec 175x1000x600mm
Type - Pset_WallCommon - IsExternal: no; Reference: Basic Wall:NLRS_42_WA_Heraklith Tektalan A2 SmartTec 175x1000x600mm; ThermalTransmittance: 0.201183 kg/K/s3
Type - Wall Schedule LOD200 - Assembly Code: 42.10; Type Image: Raster image: Heraklith Tektalan A2.jpg; Model: Heraklith® | Tektalan A2 SmartTec is een A2 houtwolcementpaneel gecombineerd met een steenwol-plaat.; Manufacturer: Knauf Insulation B.V.; URL: www.heraklith.nl; Description: Tektalan A2 SmartTec - 175mm; phone: +31(0)162-421245; email: customerservice.nl@knaufinsulation.com; product URL: https://heraklith.nl/houtwol-producten/tektalan-a2-smarttec; warmteweerstand: 4,95 (m2.K/W); NLRS_C_Code_Brandklasse: A2-s1,d0; brandweerstand: REI 120/180 mits verwerkt tegen massief beton conform classificatierapport nr 18203 / 18204; geluidsabsorbtie: 1,00; DoP: W4302GPCPR; NLRS_C_content_creator: Knauf Insulation; NLRS_C_content_versie: V1.0
Type - Pset_Wall Schedule LOD400 - panelen per pallet: 6; Assembly Code: 42.10; Type Image: Raster image: Heraklith Tektalan A2.jpg; Model: Heraklith® | Tektalan A2 SmartTec is een A2 houtwolcementpaneel gecombineerd met een steenwol-plaat.; Manufacturer: Knauf Insulation B.V.; URL: www.heraklith.nl; Description: Tektalan A2 SmartTec - 175mm; phone: +31(0)162-421245; email: customerservice.nl@knaufinsulation.com; product URL: https://heraklith.nl/houtwol-producten/tektalan-a2-smarttec; warmteweerstand: 4,95 (m2.K/W); NLRS_C_Code_Brandklasse: A2-s1,d0; brandweerstand: REI 120/180 mits verwerkt tegen massief beton conform classificatierapport nr 18203 / 18204; geluidsabsorbtie: 1,00; DoP: W4302GPCPR; NLRS_C_content_creator: Knauf Insulation; NLRS_C_content_versie: V1.0; gewicht KG/M2: 25; pallet m2: 3.6 m2; vezelbreedte: standaard 2mm optie: 1mm; kleur: standaard natuurtint optie: Wit (RAL9003) / RAL; Druksterkte kPa: 30; Chloride gehalte: Cl3; Tolerantie: Dikte (T): (T1) +3/-2; Tolerantie: Lengte (L): (L2) +3/-5; Tolerantie: Breedte (W): (W1) +3/-3; Tolerantie: Haaksheid (S): (S2) ≤2; Tolerantie: Vlakheid (P): (P1) ≤6; Randafwerking: Isolatie: n.v.t.; Randafwerking: Houtwol: Facet: 5mm; CE-codering: WW-C2-EN 13168-L2-W1-T1-S2-P1-CS(10/Y)30-TR7,5-Cl3
Classification: 42.10 (Uniformat)
Pset_WallCommon - ExtendToStructure: no; LoadBearing: no
Wall Schedule LOD200 - Type: Basic Wall: NLRS_42_WA_Heraklith Tektalan A2 SmartTec 175x1000x600mm
Pset_Wall Schedule LOD400 - Type: Basic Wall: NLRS_42_WA_Heraklith Tektalan A2 SmartTec 175x1000x600mm

# IfcWallStandardCase: Basic Wall:NLRS_42_WA_Heraklith Tektalan A2 SmartTec 200x1000x600mm, Basic Wall:NLRS_42_WA_Heraklith Tektalan A2 SmartTec 200x1000x600mm:929886
In: 00 begane grond
Type - PredefinedType: STANDARD; Material: Heraklith® I Tektalan A2 - Steenwol 190 mm, Heraklith® I Tektalan A2 - Houtwollaag - 1000x600mm 10 mm
Type - Pset_ElementShading - Roughness: 304.8 mm
Type - Pset_ManufacturerTypeInformation - Manufacturer: Knauf Insulation B.V.
Type - Pset_ProductRequirements - Category: Walls
Type - Pset_QuantityTakeOff - Reference: Basic Wall:NLRS_42_WA_Heraklith Tektalan A2 SmartTec 200x1000x600mm
Type - Pset_ReinforcementBarPitchOfWall - Description: Tektalan A2 SmartTec - 200mm; Reference: Basic Wall:NLRS_42_WA_Heraklith Tektalan A2 SmartTec 200x1000x600mm
Type - Pset_WallCommon - IsExternal: no; Reference: Basic Wall:NLRS_42_WA_Heraklith Tektalan A2 SmartTec 200x1000x600mm; ThermalTransmittance: 0.175258 kg/K/s3
Type - Wall Schedule LOD200 - Assembly Code: 42.10; Type Image: Raster image: Heraklith Tektalan A2.jpg; Model: Heraklith® | Tektalan A2 SmartTec is een A2 houtwolcementpaneel gecombineerd met een steenwol-plaat.; Manufacturer: Knauf Insulation B.V.; URL: www.heraklith.nl; Description: Tektalan A2 SmartTec - 200mm; phone: +31(0)162-421245; email: customerservice.nl@knaufinsulation.com; product URL: https://heraklith.nl/houtwol-producten/tektalan-a2-smarttec; warmteweerstand: 5,70 (m2.K/W); NLRS_C_Code_Brandklasse: A2-s1,d0; brandweerstand: REI 120/180 mits verwerkt tegen massief beton conform classificatierapport nr 18203 / 18204; geluidsabsorbtie: 0,95; DoP: W4302GPCPR; NLRS_C_content_creator: Knauf Insulation; NLRS_C_content_versie: V1.0
Type - Pset_Wall Schedule LOD400 - panelen per pallet: 5; Assembly Code: 42.10; Type Image: Raster image: Heraklith Tektalan A2.jpg; Model: Heraklith® | Tektalan A2 SmartTec is een A2 houtwolcementpaneel gecombineerd met een steenwol-plaat.; Manufacturer: Knauf Insulation B.V.; URL: www.heraklith.nl; Description: Tektalan A2 SmartTec - 200mm; phone: +31(0)162-421245; email: customerservice.nl@knaufinsulation.com; product URL: https://heraklith.nl/houtwol-producten/tektalan-a2-smarttec; warmteweerstand: 5,70 (m2.K/W); NLRS_C_Code_Brandklasse: A2-s1,d0; brandweerstand: REI 120/180 mits verwerkt tegen massief beton conform classificatierapport nr 18203 / 18204; geluidsabsorbtie: 0,95; DoP: W4302GPCPR; NLRS_C_content_creator: Knauf Insulation; NLRS_C_content_versie: V1.0; gewicht KG/M2: 25.5; pallet m2: 3 m2; vezelbreedte: standaard 2mm optie: 1mm; kleur: standaard natuurtint optie: Wit (RAL9003) / RAL; Druksterkte kPa: 30; Chloride gehalte: Cl3; Tolerantie: Dikte (T): (T1) +3/-2; Tolerantie: Lengte (L): (L2) +3/-5; Tolerantie: Breedte (W): (W1) +3/-3; Tolerantie: Haaksheid (S): (S2) ≤2; Tolerantie: Vlakheid (P): (P1) ≤6; Randafwerking: Isolatie: n.v.t.; Randafwerking: Houtwol: Facet: 5mm; CE-codering: WW-C2-EN 13168-L2-W1-T1-S2-P1-CS(10/Y)30-TR7,5-Cl3
Classification: 42.10 (Uniformat)
Pset_WallCommon - ExtendToStructure: no; LoadBearing: no
Wall Schedule LOD200 - Type: Basic Wall: NLRS_42_WA_Heraklith Tektalan A2 SmartTec 200x1000x600mm
Pset_Wall Schedule LOD400 - Type: Basic Wall: NLRS_42_WA_Heraklith Tektalan A2 SmartTec 200x1000x600mm

# IfcWallStandardCase: Basic Wall:NLRS_42_WA_Heraklith Tektalan A2 SmartTec 225x1000x600mm, Basic Wall:NLRS_42_WA_Heraklith Tektalan A2 SmartTec 225x1000x600mm:929911
In: 00 begane grond
Type - PredefinedType: STANDARD; Material: Heraklith® I Tektalan A2 - Steenwol 215 mm, Heraklith® I Tektalan A2 - Houtwollaag - 1000x600mm 10 mm
Type - Pset_ElementShading - Roughness: 304.8 mm
Type - Pset_ManufacturerTypeInformation - Manufacturer: Knauf Insulation B.V.
Type - Pset_ProductRequirements - Category: Walls
Type - Pset_QuantityTakeOff - Reference: Basic Wall:NLRS_42_WA_Heraklith Tektalan A2 SmartTec 225x1000x600mm
Type - Pset_ReinforcementBarPitchOfWall - Description: Tektalan A2 SmartTec - 225mm; Reference: Basic Wall:NLRS_42_WA_Heraklith Tektalan A2 SmartTec 225x1000x600mm
Type - Pset_WallCommon - IsExternal: no; Reference: Basic Wall:NLRS_42_WA_Heraklith Tektalan A2 SmartTec 225x1000x600mm; ThermalTransmittance: 0.155251 kg/K/s3
Type - Wall Schedule LOD200 - Assembly Code: 42.10; Type Image: Raster image: Heraklith Tektalan A2.jpg; Model: Heraklith® | Tektalan A2 SmartTec is een A2 houtwolcementpaneel gecombineerd met een steenwol-plaat.; Manufacturer: Knauf Insulation B.V.; URL: www.heraklith.nl; Description: Tektalan A2 SmartTec - 225mm; phone: +31(0)162-421245; email: customerservice.nl@knaufinsulation.com; product URL: https://heraklith.nl/houtwol-producten/tektalan-a2-smarttec; warmteweerstand: 6,40 (m2.K/W); NLRS_C_Code_Brandklasse: A2-s1,d0; brandweerstand: REI 120/180 mits verwerkt tegen massief beton conform classificatierapport nr 18203 / 18204; geluidsabsorbtie: 0,95; DoP: W4302GPCPR; NLRS_C_content_creator: Knauf Insulation; NLRS_C_content_versie: V1.0
Type - Pset_Wall Schedule LOD400 - panelen per pallet: 5; Assembly Code: 42.10; Type Image: Raster image: Heraklith Tektalan A2.jpg; Model: Heraklith® | Tektalan A2 SmartTec is een A2 houtwolcementpaneel gecombineerd met een steenwol-plaat.; Manufacturer: Knauf Insulation B.V.; URL: www.heraklith.nl; Description: Tektalan A2 SmartTec - 225mm; phone: +31(0)162-421245; email: customerservice.nl@knaufinsulation.com; product URL: https://heraklith.nl/houtwol-producten/tektalan-a2-smarttec; warmteweerstand: 6,40 (m2.K/W); NLRS_C_Code_Brandklasse: A2-s1,d0; brandweerstand: REI 120/180 mits verwerkt tegen massief beton conform classificatierapport nr 18203 / 18204; geluidsabsorbtie: 0,95; DoP: W4302GPCPR; NLRS_C_content_creator: Knauf Insulation; NLRS_C_content_versie: V1.0; gewicht KG/M2: 31; pallet m2: 3 m2; vezelbreedte: standaard 2mm optie: 1mm; kleur: standaard natuurtint optie: Wit (RAL9003) / RAL; Druksterkte kPa: 30; Chloride gehalte: Cl3; Tolerantie: Dikte (T): (T1) +3/-2; Tolerantie: Lengte (L): (L2) +3/-5; Tolerantie: Breedte (W): (W1) +3/-3; Tolerantie: Haaksheid (S): (S2) ≤2; Tolerantie: Vlakheid (P): (P1) ≤6; Randafwerking: Isolatie: n.v.t.; Randafwerking: Houtwol: Facet: 5mm; CE-codering: WW-C2-EN 13168-L2-W1-T1-S2-P1-CS(10/Y)30-TR7,5-Cl3
Classification: 42.10 (Uniformat)
Pset_WallCommon - ExtendToStructure: no; LoadBearing: no
Wall Schedule LOD200 - Type: Basic Wall: NLRS_42_WA_Heraklith Tektalan A2 SmartTec 225x1000x600mm
Pset_Wall Schedule LOD400 - Type: Basic Wall: NLRS_42_WA_Heraklith Tektalan A2 SmartTec 225x1000x600mm

# IfcWallStandardCase: Basic Wall:NLRS_42_WA_Heraklith Tektalan A2 SmartTec 50x1000x600mm, Basic Wall:NLRS_42_WA_Heraklith Tektalan A2 SmartTec 50x1000x600mm:905886
In: 00 begane grond
Type - PredefinedType: STANDARD; Material: Heraklith® I Tektalan A2 - Steenwol 40 mm, Heraklith® I Tektalan A2 - Houtwollaag - 1000x600mm 15 mm
Type - Pset_ElementShading - Roughness: 304.8 mm
Type - Pset_ManufacturerTypeInformation - Manufacturer: Knauf Insulation B.V.
Type - Pset_ProductRequirements - Category: Walls
Type - Pset_QuantityTakeOff - Reference: Basic Wall:NLRS_42_WA_Heraklith Tektalan A2 SmartTec 50x1000x600mm
Type - Pset_ReinforcementBarPitchOfWall - Description: Tektalan A2 SmartTec - 50mm; Reference: Basic Wall:NLRS_42_WA_Heraklith Tektalan A2 SmartTec 50x1000x600mm
Type - Pset_WallCommon - IsExternal: no; Reference: Basic Wall:NLRS_42_WA_Heraklith Tektalan A2 SmartTec 50x1000x600mm; ThermalTransmittance: 0.73913 kg/K/s3
Type - Wall Schedule LOD200 - Assembly Code: 42.10; Type Image: Raster image: Heraklith Tektalan A2.jpg; Model: Heraklith® | Tektalan A2 SmartTec is een A2 houtwolcementpaneel gecombineerd met een steenwol-plaat.; Manufacturer: Knauf Insulation B.V.; URL: www.heraklith.nl; Description: Tektalan A2 SmartTec - 50mm; phone: +31(0)162-421245; email: customerservice.nl@knaufinsulation.com; product URL: https://heraklith.nl/houtwol-producten/tektalan-a2-smarttec; warmteweerstand: 1,25 (m2.K/W); NLRS_C_Code_Brandklasse: A2-s1,d0; brandweerstand: REI 120/180 mits verwerkt tegen massief beton conform classificatierapport nr 18203 / 18204; geluidsabsorbtie: 0,95; DoP: W4302GPCPR; NLRS_C_content_creator: Knauf Insulation; NLRS_C_content_versie: V1.0
Type - Pset_Wall Schedule LOD400 - Assembly Code: 42.10; Type Image: Raster image: Heraklith Tektalan A2.jpg; Model: Heraklith® | Tektalan A2 SmartTec is een A2 houtwolcementpaneel gecombineerd met een steenwol-plaat.; Manufacturer: Knauf Insulation B.V.; URL: www.heraklith.nl; Description: Tektalan A2 SmartTec - 50mm; phone: +31(0)162-421245; email: customerservice.nl@knaufinsulation.com; product URL: https://heraklith.nl/houtwol-producten/tektalan-a2-smarttec; warmteweerstand: 1,25 (m2.K/W); NLRS_C_Code_Brandklasse: A2-s1,d0; brandweerstand: REI 120/180 mits verwerkt tegen massief beton conform classificatierapport nr 18203 / 18204; geluidsabsorbtie: 0,95; DoP: W4302GPCPR; NLRS_C_content_creator: Knauf Insulation; NLRS_C_content_versie: V1.0; gewicht KG/M2: 11; panelen per pallet: 22; pallet m2: 13.2 m2; vezelbreedte: standaard 2mm optie: 1mm; kleur: standaard natuurtint optie: Wit (RAL9003) / RAL; Druksterkte kPa: 30; Chloride gehalte: Cl3; Tolerantie: Dikte (T): (T1) +3/-2; Tolerantie: Lengte (L): (L2) +3/-5; Tolerantie: Breedte (W): (W1) +3/-3; Tolerantie: Haaksheid (S): (S2) ≤2; Tolerantie: Vlakheid (P): (P1) ≤6; Randafwerking: Isolatie: n.v.t.; Randafwerking: Houtwol: Facet: 5mm; CE-codering: WW-C2-EN 13168-L2-W1-T1-S2-P1-CS(10/Y)30-TR7,5-Cl3
Classification: 42.10 (Uniformat)
Pset_WallCommon - ExtendToStructure: no; LoadBearing: no
Wall Schedule LOD200 - Type: Basic Wall: NLRS_42_WA_Heraklith Tektalan A2 SmartTec 50x1000x600mm
Pset_Wall Schedule LOD400 - Type: Basic Wall: NLRS_42_WA_Heraklith Tektalan A2 SmartTec 50x1000x600mm

# IfcWallStandardCase: Basic Wall:NLRS_42_WA_Heraklith Tektalan A2 SmartTec 75x1000x600mm, Basic Wall:NLRS_42_WA_Heraklith Tektalan A2 SmartTec 75x1000x600mm:929516
In: 00 begane grond
Type - PredefinedType: STANDARD; Material: Heraklith® I Tektalan A2 - Steenwol 65 mm, Heraklith® I Tektalan A2 - Houtwollaag - 1000x600mm 15 mm
Type - Pset_ElementShading - Roughness: 304.8 mm
Type - Pset_ManufacturerTypeInformation - Manufacturer: Knauf Insulation B.V.
Type - Pset_ProductRequirements - Category: Walls
Type - Pset_QuantityTakeOff - Reference: Basic Wall:NLRS_42_WA_Heraklith Tektalan A2 SmartTec 75x1000x600mm
Type - Pset_ReinforcementBarPitchOfWall - Description: Tektalan A2 SmartTec - 75mm; Reference: Basic Wall:NLRS_42_WA_Heraklith Tektalan A2 SmartTec 75x1000x600mm
Type - Pset_WallCommon - IsExternal: no; Reference: Basic Wall:NLRS_42_WA_Heraklith Tektalan A2 SmartTec 75x1000x600mm; ThermalTransmittance: 0.478873 kg/K/s3
Type - Wall Schedule LOD200 - Assembly Code: 42.10; Type Image: Raster image: Heraklith Tektalan A2.jpg; Model: Heraklith® | Tektalan A2 SmartTec is een A2 houtwolcementpaneel gecombineerd met een steenwol-plaat.; Manufacturer: Knauf Insulation B.V.; URL: www.heraklith.nl; Description: Tektalan A2 SmartTec - 75mm; phone: +31(0)162-421245; email: customerservice.nl@knaufinsulation.com; product URL: https://heraklith.nl/houtwol-producten/tektalan-a2-smarttec; warmteweerstand: 2,00 (m2.K/W); NLRS_C_Code_Brandklasse: A2-s1,d0; brandweerstand: REI 120/180 mits verwerkt tegen massief beton conform classificatierapport nr 18203 / 18204; geluidsabsorbtie: 0,95; DoP: W4302GPCPR; NLRS_C_content_creator: Knauf Insulation; NLRS_C_content_versie: V1.0
Type - Pset_Wall Schedule LOD400 - Assembly Code: 42.10; Type Image: Raster image: Heraklith Tektalan A2.jpg; Model: Heraklith® | Tektalan A2 SmartTec is een A2 houtwolcementpaneel gecombineerd met een steenwol-plaat.; Manufacturer: Knauf Insulation B.V.; URL: www.heraklith.nl; Description: Tektalan A2 SmartTec - 75mm; phone: +31(0)162-421245; email: customerservice.nl@knaufinsulation.com; product URL: https://heraklith.nl/houtwol-producten/tektalan-a2-smarttec; warmteweerstand: 2,00 (m2.K/W); NLRS_C_Code_Brandklasse: A2-s1,d0; brandweerstand: REI 120/180 mits verwerkt tegen massief beton conform classificatierapport nr 18203 / 18204; geluidsabsorbtie: 0,95; DoP: W4302GPCPR; NLRS_C_content_creator: Knauf Insulation; NLRS_C_content_versie: V1.0; gewicht KG/M2: 14; panelen per pallet: 14; pallet m2: 8.4 m2; vezelbreedte: standaard 2mm optie: 1mm; kleur: standaard natuurtint optie: Wit (RAL9003) / RAL; Druksterkte kPa: 30; Chloride gehalte: Cl3; Tolerantie: Dikte (T): (T1) +3/-2; Tolerantie: Lengte (L): (L2) +3/-5; Tolerantie: Breedte (W): (W1) +3/-3; Tolerantie: Haaksheid (S): (S2) ≤2; Tolerantie: Vlakheid (P): (P1) ≤6; Randafwerking: Isolatie: n.v.t.; Randafwerking: Houtwol: Facet: 5mm; CE-codering: WW-C2-EN 13168-L2-W1-T1-S2-P1-CS(10/Y)30-TR7,5-Cl3
Classification: 42.10 (Uniformat)
Pset_WallCommon - ExtendToStructure: no; LoadBearing: no
Wall Schedule LOD200 - Type: Basic Wall: NLRS_42_WA_Heraklith Tektalan A2 SmartTec 75x1000x600mm
Pset_Wall Schedule LOD400 - Type: Basic Wall: NLRS_42_WA_Heraklith Tektalan A2 SmartTec 75x1000x600mm
